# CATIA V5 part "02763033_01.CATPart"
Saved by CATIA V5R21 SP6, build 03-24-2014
Part number: 02763033_01
Bounding box of the stored display mesh (mm): x -12 to 12, y -12 to 12, z -131 to 131
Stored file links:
  C:\Program Files (x86)\Trace Software\PartsXML Tools\RobotPartsAuto\MOTION_1402216426\CAD\Temp\02763033_01.CATPart

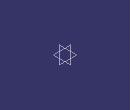
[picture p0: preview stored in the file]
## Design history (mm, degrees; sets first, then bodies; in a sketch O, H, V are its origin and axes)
AxisSystem1: origin (0, 0, 0), X (1, 0, 0), Y (0, 1, 0), Z (0, 0, 1)
Body1 "02763033_01" (main body)
  Solid1: solid without history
